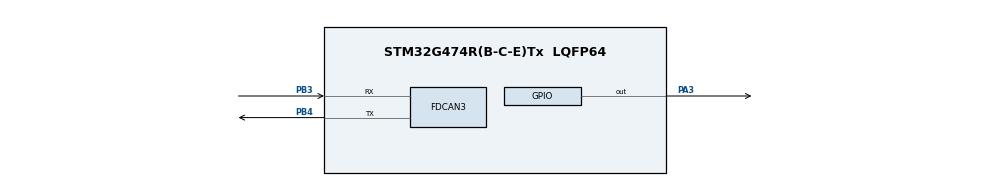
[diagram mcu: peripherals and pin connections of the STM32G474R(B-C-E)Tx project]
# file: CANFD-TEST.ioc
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FDCAN3.AutoRetransmission=ENABLE
FDCAN3.CalculateBaudRateNominal=500000
FDCAN3.CalculateTimeBitNominal=2000
FDCAN3.CalculateTimeQuantumNominal=200.0
FDCAN3.DataPrescaler=17
FDCAN3.DataTimeSeg1=7
FDCAN3.DataTimeSeg2=2
FDCAN3.ExtFiltersNbr=1
FDCAN3.FrameFormat=FDCAN_FRAME_FD_NO_BRS
FDCAN3.NominalPrescaler=17
FDCAN3.NominalTimeSeg1=7
FDCAN3.NominalTimeSeg2=2
FDCAN3.StdFiltersNbr=1
Mcu.Family=STM32G4
Mcu.Name=STM32G474R(B-C-E)Tx
Mcu.Package=LQFP64
NVIC.FDCAN3_IT0_IRQn=true\:0\:0\:false\:false\:true\:true\:true\:true
NVIC.FDCAN3_IT1_IRQn=true\:0\:0\:false\:false\:true\:true\:true\:true
NVIC.PriorityGroup=NVIC_PRIORITYGROUP_4
PA13.Mode=Serial_Wire
PA13.Signal=SYS_JTMS-SWDIO
PA14.Mode=Serial_Wire
PA14.Signal=SYS_JTCK-SWCLK
PA3.Signal=GPIO_Output
PB3.Mode=FDCAN_Activate
PB3.Signal=FDCAN3_RX
PB4.Mode=FDCAN_Activate
PB4.Signal=FDCAN3_TX
PF0-OSC_IN.Mode=HSE-External-Oscillator
PF0-OSC_IN.Signal=RCC_OSC_IN
PF1-OSC_OUT.Mode=HSE-External-Oscillator
PF1-OSC_OUT.Signal=RCC_OSC_OUT
ProjectManager.HeapSize=0x200
ProjectManager.StackSize=0x400
ProjectManager.TargetToolchain=STM32CubeIDE
RCC.ADC12Freq_Value=170000000
RCC.ADC345Freq_Value=170000000
RCC.AHBFreq_Value=170000000
RCC.APB1Freq_Value=170000000
RCC.APB1TimFreq_Value=170000000
RCC.APB2Freq_Value=170000000
RCC.APB2TimFreq_Value=170000000
RCC.CortexFreq_Value=170000000
RCC.EXTERNAL_CLOCK_VALUE=12288000
RCC.FDCANCLockSelection=RCC_FDCANCLKSOURCE_PLL
RCC.HCLKFreq_Value=170000000
RCC.HSE_VALUE=8000000
RCC.HSI48_VALUE=48000000
RCC.HSI_VALUE=16000000
RCC.LSE_VALUE=32768
RCC.PLLM=RCC_PLLM_DIV4
RCC.PLLN=85
RCC.PLLQ=RCC_PLLQ_DIV4
RCC.SYSCLKFreq_VALUE=170000000
RCC.SYSCLKSource=RCC_SYSCLKSOURCE_PLLCLK
RCC.USBFreq_Value=85000000
RCC.VCOOutputFreq_Value=340000000
VP_SYS_VS_DBSignals.Mode=DisableDeadBatterySignals
board=custom

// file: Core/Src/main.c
/* USER CODE BEGIN Header */
/**
  ******************************************************************************
  * @file           : main.c
  * @brief          : Main program body
  ******************************************************************************
  * @attention
  *
  * Copyright (c) 2026 STMicroelectronics.
  * All rights reserved.
  *
  * This software is licensed under terms that can be found in the LICENSE file
  * in the root directory of this software component.
  * If no LICENSE file comes with this software, it is provided AS-IS.
  *
  ******************************************************************************
  */
/* USER CODE END Header */
#include "main.h"
#include "fdcan.h"
#include "gpio.h"

/* USER CODE BEGIN Includes */
#include "MyCANFD.h"
/* USER CODE END Includes */

/* USER CODE BEGIN PD */
uint8_t data[8]={0x00,0x01,0x02,0x03};
/* USER CODE END PD */

void SystemClock_Config(void);

int main(void)
{

  /* MCU Configuration--------------------------------------------------------*/

  /* Reset of all peripherals, Initializes the Flash interface and the Systick. */
  HAL_Init();

  /* Configure the system clock */
  SystemClock_Config();

  /* Initialize all configured peripherals */
  MX_GPIO_Init();
  MX_FDCAN3_Init();
  /* USER CODE BEGIN 2 */
  MyCANFD_Init();
  /* USER CODE END 2 */

  /* Infinite loop */
  while (1)
  {

    /* USER CODE BEGIN 3 */
	  HAL_GPIO_WritePin(GPIOA, GPIO_PIN_3, GPIO_PIN_RESET); // 强制拉低看看亮不亮
      HAL_Delay(10);
//      HAL_GPIO_WritePin(GPIOA, GPIO_PIN_3, GPIO_PIN_SET);   // 强制拉高看看灭不灭
	  HAL_Delay(10);
	  /* 把接收到的数据以CANFD发送回去 */
	  if(CANFD_MODE==1)
	  {
        CANFD_MODE=0;
    MyCANFD_Transmit(0X123,data,FDCAN_DLC_BYTES_64,FDCAN_EXTENDED_ID);

	  FDCAN_TxHeader.DataLength = FDCAN_RxHeader.DataLength;
	  FDCAN_TxHeader.Identifier = FDCAN_RxHeader.Identifier;
	  FDCAN_TxHeader.IdType=FDCAN_RxHeader.IdType;
	  if(HAL_FDCAN_AddMessageToTxFifoQ(&hfdcan3, &FDCAN_TxHeader, can3_rxbuf) != HAL_OK)
	      {
	         Error_Handler();
	       }
	  }
  }
  /* USER CODE END 3 */
}

void SystemClock_Config(void)
{
  RCC_OscInitTypeDef RCC_OscInitStruct = {0};
  RCC_ClkInitTypeDef RCC_ClkInitStruct = {0};

  /** Configure the main internal regulator output voltage
  */
  HAL_PWREx_ControlVoltageScaling(PWR_REGULATOR_VOLTAGE_SCALE1);

  /** Initializes the RCC Oscillators according to the specified parameters
  * in the RCC_OscInitTypeDef structure.
  */
  RCC_OscInitStruct.OscillatorType = RCC_OSCILLATORTYPE_HSI;
  RCC_OscInitStruct.HSIState = RCC_HSI_ON;
  RCC_OscInitStruct.HSICalibrationValue = RCC_HSICALIBRATION_DEFAULT;
  RCC_OscInitStruct.PLL.PLLState = RCC_PLL_ON;
  RCC_OscInitStruct.PLL.PLLSource = RCC_PLLSOURCE_HSI;
  RCC_OscInitStruct.PLL.PLLM = RCC_PLLM_DIV1;
  RCC_OscInitStruct.PLL.PLLN = 10;
  RCC_OscInitStruct.PLL.PLLP = RCC_PLLP_DIV2;
  RCC_OscInitStruct.PLL.PLLQ = RCC_PLLQ_DIV2;
  RCC_OscInitStruct.PLL.PLLR = RCC_PLLR_DIV2;
  if (HAL_RCC_OscConfig(&RCC_OscInitStruct) != HAL_OK)
  {
    Error_Handler();
  }

  /** Initializes the CPU, AHB and APB buses clocks
  */
  RCC_ClkInitStruct.ClockType = RCC_CLOCKTYPE_HCLK|RCC_CLOCKTYPE_SYSCLK
                              |RCC_CLOCKTYPE_PCLK1|RCC_CLOCKTYPE_PCLK2;
  RCC_ClkInitStruct.SYSCLKSource = RCC_SYSCLKSOURCE_PLLCLK;
  RCC_ClkInitStruct.AHBCLKDivider = RCC_SYSCLK_DIV1;
  RCC_ClkInitStruct.APB1CLKDivider = RCC_HCLK_DIV1;
  RCC_ClkInitStruct.APB2CLKDivider = RCC_HCLK_DIV1;

  if (HAL_RCC_ClockConfig(&RCC_ClkInitStruct, FLASH_LATENCY_2) != HAL_OK)
  {
    Error_Handler();
  }
}

void Error_Handler(void)
{
  /* USER CODE BEGIN Error_Handler_Debug */
  /* User can add his own implementation to report the HAL error return state */
  __disable_irq();
  while (1)
  {
	  HAL_GPIO_WritePin(GPIOA, GPIO_PIN_3, GPIO_PIN_RESET); // 强制拉低看看亮不亮
      HAL_Delay(1000);
     HAL_GPIO_WritePin(GPIOA, GPIO_PIN_3, GPIO_PIN_SET);   // 强制拉高看看灭不灭
	  HAL_Delay(1000);
  }
  /* USER CODE END Error_Handler_Debug */
}
